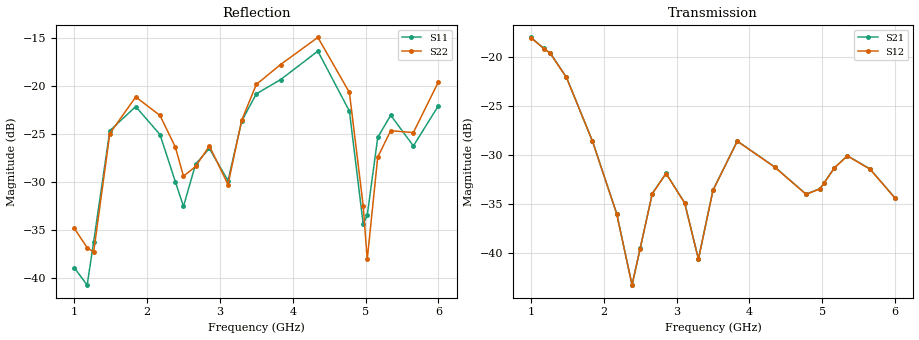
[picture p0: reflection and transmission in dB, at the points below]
!Agilent Technologies,E8364B,MY43040528,A.07.50.67
!Agilent E8364B: A.07.50.67
!Date: Sunday, March 01, 2026 20:29:44
!Correction: S11(Full 2 Port(1,2))
!S21(Full 2 Port(1,2))
!S12(Full 2 Port(1,2))
!S22(Full 2 Port(1,2))
!S2P File: Measurements: S11, S21, S12, S22:
# Hz S  dB  R 50
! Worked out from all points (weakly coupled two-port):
!   451 points, 1 GHz to 6 GHz, reference 50 ohm
!   highest |S21| = -17.99 dB at 1 GHz (marker M1); lowest = -43.3 dB at 2.389 GHz (marker M2)
!   lowest |S11| = -40.7 dB at 1.178 GHz (marker M3), VSWR 1.02, Z = 49.4 + j0.651 ohm
!   |S11| at or under -10 dB: start of sweep to end of sweep
!   |S22| runs from -38.0 to -14.8 dB; largest |S21 - S12| = 0.00032
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1e9  -38.90 73.2  -17.99 25.6  -18.01 25.6  -34.80 11.9
1.177778e9  -40.72 134.3  -19.12 -27.8  -19.13 -27.9  -36.82 37.3
1.266667e9  -36.23 175.1  -19.61 -56.9  -19.63 -56.9  -37.29 73.9
1.488889e9  -24.66 154.0  -22.08 -132.3  -22.09 -132.4  -24.96 69.7
1.844444e9  -22.15 91.2  -28.58 116.2  -28.59 116.2  -21.15 -7.2
2.177778e9  -25.07 54.8  -36.00 13.0  -36.02 13.0  -23.08 -61.6
2.388889e9  -29.98 43.0  -43.30 -119.5  -43.32 -119.6  -26.38 -91.0
2.5e9  -32.54 63.9  -39.57 145.8  -39.59 145.7  -29.39 -91.0
2.666667e9  -28.13 81.6  -33.96 59.5  -33.98 59.5  -28.38 -75.1
2.855556e9  -26.51 58.7  -31.89 -20.7  -31.91 -20.7  -26.25 -98.7
3.111111e9  -29.85 74.8  -34.91 -116.0  -34.93 -116.0  -30.26 -97.1
3.3e9  -23.65 79.5  -40.65 -133.5  -40.67 -133.4  -23.56 -90.8
3.5e9  -20.83 53.4  -33.60 -154.5  -33.63 -154.5  -19.85 -124.4
3.833333e9  -19.35 28.8  -28.59 83.4  -28.61 83.3  -17.78 -166.5
4.344444e9  -16.39 -38.6  -31.22 -101.5  -31.24 -101.5  -14.96 107.4
4.777778e9  -22.63 -106.8  -34.02 72.9  -34.04 72.9  -20.69 19.2
4.966667e9  -34.35 -90.5  -33.46 -33.5  -33.48 -33.5  -32.45 -2.8
5.022222e9  -33.47 -48.1  -32.90 -64.3  -32.92 -64.3  -38.05 42.4
5.166667e9  -25.36 -40.8  -31.32 -139.1  -31.34 -139.2  -27.41 80.2
5.344444e9  -23.05 -67.9  -30.09 138.1  -30.11 138.0  -24.66 50.4
5.655556e9  -26.25 -78.1  -31.44 11.0  -31.47 11.0  -24.86 45.4
6e9  -22.06 -81.8  -34.42 -83.7  -34.44 -83.7  -19.58 6.2
